VERSION 5.7 ;
  NOWIREEXTENSIONATPIN ON ;
  DIVIDERCHAR "/" ;
  BUSBITCHARS "[]" ;
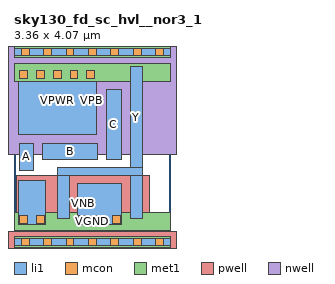
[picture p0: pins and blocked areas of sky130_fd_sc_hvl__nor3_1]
MACRO sky130_fd_sc_hvl__nor3_1
  CLASS BLOCK ;
  FOREIGN sky130_fd_sc_hvl__nor3_1 ;
  ORIGIN 0.000 0.000 ;
  SIZE 3.360 BY 4.070 ;
  PIN A
    ANTENNAGATEAREA 1.125000 ;
    PORT
      LAYER li1 ;
        RECT 0.125 1.525 0.425 2.120 ;
    END
  END A
  PIN B
    ANTENNAGATEAREA 1.125000 ;
    PORT
      LAYER li1 ;
        RECT 0.605 1.775 1.795 2.120 ;
    END
  END B
  PIN C
    ANTENNAGATEAREA 1.125000 ;
    PORT
      LAYER li1 ;
        RECT 1.975 1.775 2.305 3.260 ;
    END
  END C
  PIN VGND
    USE GROUND ;
    PORT
      LAYER li1 ;
        RECT 0.090 0.365 0.680 1.325 ;
        RECT 1.360 0.365 2.310 1.245 ;
      LAYER mcon ;
        RECT 0.120 0.395 0.290 0.565 ;
        RECT 0.480 0.395 0.650 0.565 ;
        RECT 1.390 0.395 1.560 0.565 ;
        RECT 1.750 0.395 1.920 0.565 ;
        RECT 2.110 0.395 2.280 0.565 ;
      LAYER met1 ;
        RECT 0.000 0.255 3.360 0.625 ;
    END
  END VGND
  PIN VNB
    ANTENNADIFFAREA 0.571200 ;
    PORT
      LAYER pwell ;
        RECT 0.060 0.215 2.910 1.415 ;
        RECT -0.130 -0.215 3.490 0.215 ;
      LAYER li1 ;
        RECT 0.000 -0.085 3.360 0.085 ;
      LAYER mcon ;
        RECT 0.155 -0.085 0.325 0.085 ;
        RECT 0.635 -0.085 0.805 0.085 ;
        RECT 1.115 -0.085 1.285 0.085 ;
        RECT 1.595 -0.085 1.765 0.085 ;
        RECT 2.075 -0.085 2.245 0.085 ;
        RECT 2.555 -0.085 2.725 0.085 ;
        RECT 3.035 -0.085 3.205 0.085 ;
      LAYER met1 ;
        RECT 0.000 -0.115 3.360 0.115 ;
    END
  END VNB
  PIN VPB
    ANTENNADIFFAREA 0.571200 ;
    PORT
      LAYER nwell ;
        RECT -0.330 1.885 3.690 4.485 ;
      LAYER li1 ;
        RECT 0.000 3.985 3.360 4.155 ;
      LAYER mcon ;
        RECT 0.155 3.985 0.325 4.155 ;
        RECT 0.635 3.985 0.805 4.155 ;
        RECT 1.115 3.985 1.285 4.155 ;
        RECT 1.595 3.985 1.765 4.155 ;
        RECT 2.075 3.985 2.245 4.155 ;
        RECT 2.555 3.985 2.725 4.155 ;
        RECT 3.035 3.985 3.205 4.155 ;
      LAYER met1 ;
        RECT 0.000 3.955 3.360 4.185 ;
    END
  END VPB
  PIN VPWR
    USE POWER ;
    PORT
      LAYER li1 ;
        RECT 0.090 2.300 1.760 3.755 ;
      LAYER mcon ;
        RECT 0.120 3.505 0.290 3.675 ;
        RECT 0.480 3.505 0.650 3.675 ;
        RECT 0.840 3.505 1.010 3.675 ;
        RECT 1.200 3.505 1.370 3.675 ;
        RECT 1.560 3.505 1.730 3.675 ;
      LAYER met1 ;
        RECT 0.000 3.445 3.360 3.815 ;
    END
  END VPWR
  PIN Y
    ANTENNADIFFAREA 0.836250 ;
    PORT
      LAYER li1 ;
        RECT 2.490 1.595 2.755 3.755 ;
        RECT 0.930 1.425 2.755 1.595 ;
        RECT 0.930 0.495 1.180 1.425 ;
        RECT 2.490 0.495 2.755 1.425 ;
    END
  END Y
END sky130_fd_sc_hvl__nor3_1
END LIBRARY

